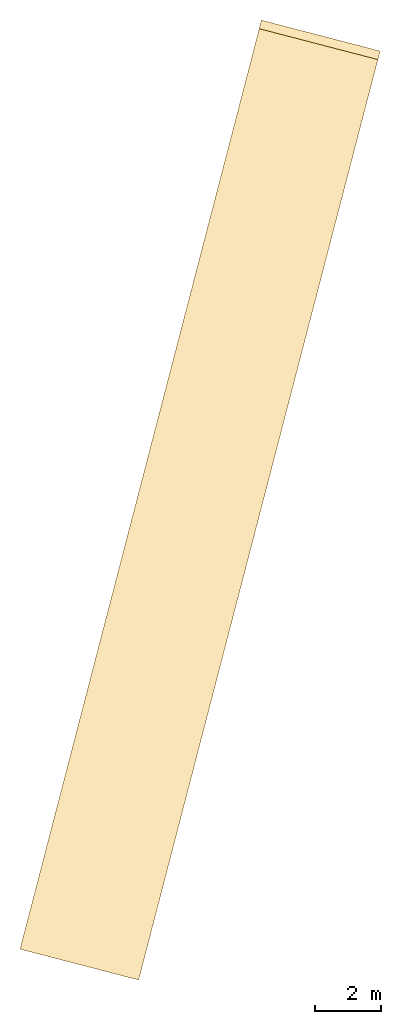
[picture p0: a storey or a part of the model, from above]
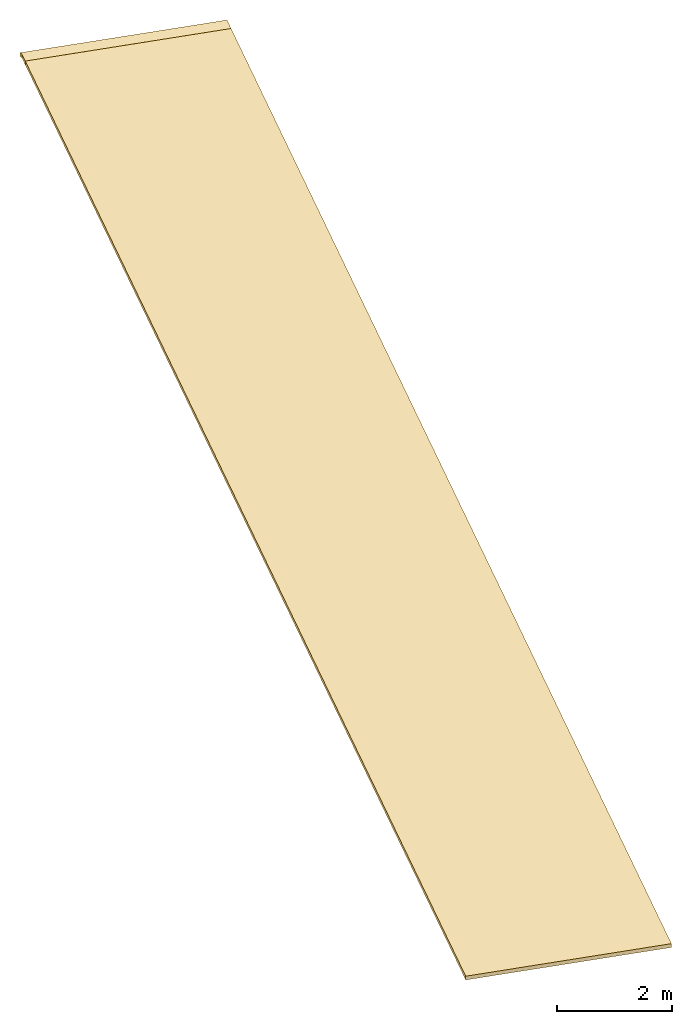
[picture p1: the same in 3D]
Properties of the parts of a building model (IFC2X3)

# File
Description: ViewDefinition [CoordinationView_V2.0, QuantityTakeOffAddOnView]
File name: zv001-a-200-1-0003.ifc (Edited by Naviate Simple BIM 2022 version 6)
Time: 2026-01-09T13:08:05+01:00
Written by: ODA SDAI 24.12
Made in: Autodesk Revit 25.4.30.30 (ENU) - IFC 25.4.0.27

# IfcProject, 10001574
LongName: ENZV Kommersielt areal innland (KAI); Phase: Hovedprosjekt: 01.12.2018

# IfcSite (2)
RefElevation: 0 mm
Name | RefLatitude | RefLongitude
ENZV | 59, 54, 57, 601318 | 10, 44, 59, 999999 | Identity Data - Inventarnr.: ZV001; Building Name: ZV001; CQIncludeDoorSwing: no; CQIncludeRoomNumber: no; CQIncludeRoomNumberWindows: no; CQIncludeWindowSwing: no; Workset: Project Info; Organization Description: BIM 360://Avinor - Stavanger lufthavn/ENZV_ARK_bygg A.rvt; Prosjekt: Stavanger lufthavn, Sola; Text - 02_IfcSite: STAVANGER LUFTHAVN; 01_Modellfil: zv001-a-200-1-0003.rvt; Prosjektleder: Livar Husveg; Tiltaket gjelder: Kommersielt areal innland, KAI; Other - Project Number: 10001574; CQDoorSwingCodes: Left=V;Right=H;notMirrored =L;mirrored =R; Project Issue Date: Tilbudsprosjekt: 22.07.2018; CQWindowSwingCodes: Left=Rettv.;Right=Speilv.; Category: Project Information; Project Address: Enter address here; CQPhaseFilter: Existing:True;New Construction:True;Fase 2.0:True;Fase 3.0:True;Fase 3.9:True;Fase 4.0:True;Fase 5.1:True;Fase 5.2:True;Fase 5.3:True;Fase 5.4:True;Fase 5.9:True;Fase 5.10:True;Fase plot tegninger:True;Fase 6.0:True;; CQIncludeTemporaryDoors: no; Project Name: ENZV Kommersielt areal innland (KAI); Project Status: Hovedprosjekt: 01.12.2018; Tiltakshavers navn: Livar Husveg
Default | 42, 24, 53, 508911 | -71, -15, -29, -58837 | Pset_ProductRequirements - Category: Project Information

# IfcBuilding (2)
Name | NumberOfStoreys
ZV001 | 8 | LongName: ZV001; Identity Data - Inventarnr.: ZV001; Building Name: ZV001; CQIncludeDoorSwing: no; CQIncludeRoomNumber: no; CQIncludeRoomNumberWindows: no; CQIncludeWindowSwing: no; Workset: Project Info; Organization Description: BIM 360://Avinor - Stavanger lufthavn/ENZV_ARK_bygg A.rvt; Prosjekt: Stavanger lufthavn, Sola; Text - 02_IfcSite: STAVANGER LUFTHAVN; 01_Modellfil: zv001-a-200-1-0003.rvt; Prosjektleder: Livar Husveg; Tiltaket gjelder: Kommersielt areal innland, KAI; Other - Project Number: 10001574; CQDoorSwingCodes: Left=V;Right=H;notMirrored =L;mirrored =R; Project Issue Date: Tilbudsprosjekt: 22.07.2018; CQWindowSwingCodes: Left=Rettv.;Right=Speilv.; Category: Project Information; Project Address: Enter address here; CQPhaseFilter: Existing:True;New Construction:True;Fase 2.0:True;Fase 3.0:True;Fase 3.9:True;Fase 4.0:True;Fase 5.1:True;Fase 5.2:True;Fase 5.3:True;Fase 5.4:True;Fase 5.9:True;Fase 5.10:True;Fase plot tegninger:True;Fase 6.0:True;; CQIncludeTemporaryDoors: no; Project Name: ENZV Kommersielt areal innland (KAI); Project Status: Hovedprosjekt: 01.12.2018; Tiltakshavers navn: Livar Husveg
 | 4 | Pset_ProductRequirements - Category: Project Information

# IfcBuildingStorey: Level:8mm Nivåhode Lokale Koter (2)
In: ZV001
Identity Data - Structural: no; Building Story: yes; Workset: Shared Levels and Grids
Graphics(Type) - Line Pattern: Centre; Color: 0; Symbol at End 1 Default: no; Symbol at End 2 Default: yes; Line Weight: 1; Symbol: View - Nivåhode1 : Nivåhode Trekant 2
Identity Data(Type) - Workset: Level Types; Type Name: 8mm Nivåhode Lokale Koter
Constraints(Type) - Elevation Base: Project Base Point
Other - Type Id: 305; Category: Levels; Family and Type: Level: 8mm Nivåhode Lokale Koter; Family: Level; Type: 8mm Nivåhode Lokale Koter
Pset_AirSideSystemInformation - sets with these values: 2
Other(Type) - Category: Levels; Family Name: Level
Phasing - Fagkode: ARK
Name | LongName = Identity Data, Name = Pset_AirSideSystemInformation, Name = Etasjekoder | Elevation (mm) = Constraints, Elevation (mm) | Computation Height (mm)
H01 | H01 | 5100 | 1200
H02 | H02 | 9300 | 0

# IfcBuildingStorey: Level:NO_Nivå_meter-Project, PLAN 01. ETG
LongName: PLAN 01. ETG; Elevation: 5100 mm
Pset_AirSideSystemInformation - Name: PLAN 01. ETG
Pset_ProductRequirements - Name: PLAN 01. ETG; Category: Levels

# IfcBuildingElementProxy: Generic Models 4:Generic Models 4, Generic Models 4:Generic Models 4:919170
In: PLAN 01. ETG
Type - Material: Hvit
Type - Other - Category: Generic Models; Family Name: Generic Models 4
Type - Identity Data - Type Name: Generic Models 4; Workset: Workset1
ePset_LocationTool - Splitting: RESULT
ePset_SimplebimBasicQuantities - Height (Simplebim): 450 mm; Thickness (Simplebim): 612 mm; Length (Simplebim): 1824 mm; Area, largest surface, net (Simplebim): 1.00146 m2; Volume, net (Simplebim): 0.389924 m3
ePset_Simplebim - Assembly Level: Leaf
Pset_ProductRequirements - Category: Generic Models
Pset_BuildingElementProxyCommon - Reference: Generic Models 4; sets with these values: 2

# IfcBuildingElementProxy: karusseldør Bund7:karusseldør Bund, karusseldør Bund7:karusseldør Bund:3024298
In: H01
Type - Material: Aluminium, Glass, <Unnamed>
Type - Other - Category: Generic Models; Family Name: karusseldør Bund7
Type - Identity Data - Type Name: karusseldør Bund; Workset: Workset1
Constraints - Moves With Nearby Elements: no
Pset_BuildingElementProxyCommon - Reference: karusseldør Bund; sets with these values: 2
Phasing - Phase Created: Fase 1 - Som bygget
ePset_LocationTool - Splitting: RESULT
ePset_Simplebim - Assembly Level: Leaf
ePset_SimplebimBasicQuantities - Area, largest surface, net (Simplebim): 0.935324 m2; Volume, net (Simplebim): 0.330344 m3; Thickness (Simplebim): 896 mm; Length (Simplebim): 1751 mm; Height (Simplebim): 2918 mm
Other - Type Id: 3024296; Family and Type: karusseldør Bund7: karusseldør Bund; Type: karusseldør Bund; Family: karusseldør Bund7
Group: Model Group:Karusseldør YK01:3024403

# IfcColumn: NO_S-Column_Precast_Round:Pullert ø350, NO_S-Column_Precast_Round:Pullert ø350:886020
In: PLAN 01. ETG
Type - PredefinedType: COLUMN; Material: NO_Betong - Prefab
Type - Pset_ColumnCommon - Reference: Pullert ø350; IsExternal: no; LoadBearing: yes
Type - Pset_ProductRequirements - Category: Structural Columns
Type - Pset_QuantityTakeOff - Reference: Pullert ø350
Type - Pset_ReinforcementBarPitchOfColumn - Reference: Pullert ø350
Pset_ReinforcementBarPitchOfColumn - sets with these values: 2
ePset_SimplebimBasicQuantities - Width (Simplebim): 350 mm; Depth (Simplebim): 350 mm; Volume, net (Simplebim): 0.129227 m3; Area, sides, net (Simplebim): 1.48252 m2; Weight, as steel (Simplebim): 1014.43 kg; Height (Simplebim): 1350 mm
ePset_LocationTool - Splitting: ORIGINAL
AVINOR - 03_Ansvar: RIB Norconsult; 06_Omrade: ZV000; 05_ID-nummer: +ZV000=725.0015-QM0002; 01_Lufthavnkode: ENZV; 02_Prosjekt: 10002213
ePset_Simplebim - Assembly Level: Leaf

# IfcColumn: Søyle Betong Sirkulær:350 (4)
In: H01
Type - PredefinedType: COLUMN; Material: Betong Plasstøpt - B35
Type - Other - Category: Structural Columns; Family Name: Søyle Betong Sirkulær; k1: 3.14159
Type - Dimensions - D: 350 mm; Perimeter: 1099.56 mm
Type - Identity Data - Type Name: 350; URL: www.cad-q.no; Workset: Family : Structural Columns : Søyle Betong Sirkulær
Type - Structural - Section Shape: 0
Type - Pset_ColumnCommon - LoadBearing: yes
Phasing - Phase Created: Fase 1 - Som bygget
Pset_QuantityTakeOff - Reference: 350; sets with these values: 2
Pset_ColumnCommon - IsExternal: no; Reference: 350
Identity Data - Has Association: yes; Workset: Workset1
Other - Family and Type: Søyle Betong Sirkulær: 350; Type Id: 414188; Family: Søyle Betong Sirkulær; Type: 350
Structural - Rebar Cover - Top Face: Rebar Cover 1 <25 mm>; Rebar Cover - Other Faces: Rebar Cover 1 <25 mm>; Rebar Cover - Bottom Face: Rebar Cover 1 <25 mm>
Constraints - Room Bounding: no; Moves With Grids: no; Level: H01; Base Level: H01; Top Level: H02; Column Style: Vertical
ePset_SimplebimBasicQuantities - Volume, net (Simplebim): 0.335032 m3; Area, sides, net (Simplebim): 3.84357 m2; Weight, as steel (Simplebim): 2630 kg; Width (Simplebim): 350 mm; Depth (Simplebim): 350 mm; Height (Simplebim): 3500 mm
ePset_Simplebim - Assembly Level: Leaf
Materials and Finishes - Structural Material: Betong Plasstøpt - B35
ePset_LocationTool - Splitting: RESULT
Name (Søyle Betong Sirkulær:350:...) | Column Location Mark
3049593 | P3-CM03
3049595 | P3-CM04
3049607 | P3-CM05
3049619 | P3-CM06 | Group: Model Group:Array Group 3:3049621

# IfcCovering: Compound Ceiling:ENZV_H01_Perf gipshimling 600x600mm (3)
Type - PredefinedType: CEILING
Type - Other - Category: Ceilings; Family Name: Compound Ceiling
Type - Construction - Thickness: 80 mm
Type - Graphics - Coarse Scale Fill Color: 0
Type - Identity Data - Type Mark: H-03; Type Name: ENZV_H01_Perf gipshimling 600x600mm; Workset: Ceiling Types
Type - Analytical Properties - Absorptance: 0.1; Roughness: 1
Type - Pset_CoveringCommon - TotalThickness: 80 mm
ePset_LocationTool - Splitting: RESULT
Phasing - Phase Created: Fase 1 - Som bygget
ePset_SimplebimBasicQuantities - Height (Simplebim): 80 mm
Pset_CoveringCommon - Reference: ENZV_H01_Perf gipshimling 600x600mm; Finish: Systemhimling 600x600mm;
Constraints - Room Bounding: yes
Other - Type: ENZV_H01_Perf gipshimling 600x600mm; Type Id: 389168; Family: Compound Ceiling; Family and Type: Compound Ceiling: ENZV_H01_Perf gipshimling 600x600mm
ePset_Simplebim - Assembly Level: Leaf
Pset_QuantityTakeOff - Reference: ENZV_H01_Perf gipshimling 600x600mm
Identity Data - Workset: Workset1
Name (Compound Ceiling:ENZV_H01_Perf gipshimling 600x600mm:...) | In | Volume, net (Simplebim) (m3) | Area, largest surface, net (Simplebim) (m2) | Width (Simplebim) (mm) | Length (Simplebim) (mm) | Level
3023942 | H02 | 8.49494 | 106.187 | 17552 | 26898 | H02
3049153 | H02 | 0.0789045 | 0.986301 | 2092 | 3338 | H02
3026525 | H01 | 0.469333 | 5.86664 | 3214 | 3946 | H01

# IfcCurtainWall: Curtain Wall:Curtain Wall glass 125mm ut (10)
In: H01
Type - Other - Category: Walls; Family Name: Curtain Wall
Type - Construction - Function: Exterior; Automatically Embed: yes; Join Condition: Not Defined
Type - Identity Data - Type Name: Curtain Wall glass 125mm ut; Workset: Curtain Wall Types
Type - Horizontal Grid - Adjust for Mullion Size: no
Type - Vertical Grid - Adjust for Mullion Size: no
Pset_QuantityTakeOff - Reference: Curtain Wall glass 125mm ut
Cross-Section Definition - Cross-Section: Vertical
Structural - Structural Usage: Non-bearing; Structural: no
Constraints - Base is Attached: no; Related to Mass: no; Room Bounding: yes; Top Offset: 0 mm; Top is Attached: no; Base Constraint: H01; Base Offset: 20 mm
Other - Type: Curtain Wall glass 125mm ut; Family and Type: Curtain Wall: Curtain Wall glass 125mm ut; Type Id: 386823; Family: Curtain Wall
ePset_Simplebim - Assembly Level: Topmost
Phasing - Phase Created: Fase 1 - Som bygget
Horizontal Grid - Number: 4; Angle: 0 deg; Offset: 0 mm; Justification: Beginning
Vertical Grid - Angle: 0 deg; Offset: 0 mm; Number: 4; Justification: Beginning
Pset_CurtainWallCommon - Reference: Curtain Wall glass 125mm ut; IsExternal: yes
BaseQuantities - Width: 25 mm
Name (Curtain Wall:Curtain Wall glass 125mm ut:...) | Volume, net (Simplebim) (m3) | ePset_SimplebimBasicQuantities, Height (mm) | Width (mm) | ePset_SimplebimBasicQuantities, Length (mm) | Unconnected Height (mm) = BaseQuantities, Height (mm) | CQWallGrossArea (m2) | Workset | Area (m2) = GrossSideArea (m2) | Dimensions, Length (mm)
3028790 | 73.4516 | 12410.4 | 303 | 72064.9 | 12410 | 858.837 | Workset1 | 838.989 | 72110.9 | Identity Data - Has Association: no
3038579 | 2.36117 | 4170 | 4775.25 | 7967.47 | 4170 | 242.024 | Workset1 | 37.6335 | 9024.81
3045456 | 0.613538 | 4170 | 1188.29 | 1754.17 | 4170 | 242.024 | Workset1 | 7.71461 | 1850.03
3045476 | 0.550154 | 4170 | 1162.92 | 1710.59 | 4170 | 242.024 | Workset1 | 7.506 | 1800
3045501 | 0.504609 | 4170 | 1188.35 | 1754.1 | 4170 | 242.024 | Workset1 | 7.7145 | 1850
3045579 | 0.549954 | 4170 | 1188.35 | 1754.1 | 4170 | 242.024 | Workset1 | 7.7145 | 1850
3045609 | 0.527082 | 4170 | 1140.3 | 1670.9 | 4170 | 242.024 | Workset1 | 7.31383 | 1753.92
3045628 | 0.550154 | 4170 | 1162.92 | 1710.59 | 4170 | 242.024 | Workset1 | 7.506 | 1800
3045650 | 0.442854 | 4170 | 1115.23 | 1627.63 | 4170 | 242.024 | Workset1 | 7.10524 | 1703.89
4091180 | 5.41812 | 4170 | 10163.6 | 17298.7 | 4170 | 242.024 | ARK - Innvendige arbeider | 82.5662 | 23853.9

# IfcCurtainWall: Curtain Wall:Glassvegg 24 dB (4)
In: H01
Type - Other - Category: Walls; Family Name: Curtain Wall
Type - Construction - Function: Exterior; Automatically Embed: yes; Join Condition: Not Defined
Type - Identity Data - Type Name: Glassvegg 24 dB; Workset: Curtain Wall Types; Lydklasse: R'w=24 dB; Type Mark: IVG 24 dB
Type - Horizontal Grid - Adjust for Mullion Size: no
Type - Vertical Grid - Adjust for Mullion Size: no
Cross-Section Definition - Cross-Section: Vertical
Other - Family and Type: Curtain Wall: Glassvegg 24 dB; Type: Glassvegg 24 dB; Type Id: 128838; Family: Curtain Wall
Constraints - Base is Attached: no; Related to Mass: no; Room Bounding: yes; Top Offset: 0 mm; Top is Attached: no; Base Constraint: H01
Structural - Structural Usage: Non-bearing; Structural: no
Identity Data - Workset: Workset1
ePset_Simplebim - Assembly Level: Topmost
Pset_CurtainWallCommon - Reference: Glassvegg 24 dB; IsExternal: yes
Phasing - Phase Created: Fase 1 - Som bygget
Horizontal Grid - Number: 4; Angle: 0 deg; Offset: 0 mm; Justification: Beginning
Vertical Grid - Angle: 0 deg; Offset: 0 mm; Number: 4; Justification: Beginning
Pset_QuantityTakeOff - Reference: Glassvegg 24 dB
BaseQuantities - Width: 25 mm
Name (Curtain Wall:Glassvegg 24 dB:...) | ePset_SimplebimBasicQuantities, Length (mm) | Width (mm) | Volume, net (Simplebim) (m3) | ePset_SimplebimBasicQuantities, Height (mm) = Unconnected Height (mm) = BaseQuantities, Height (mm) | Base Offset (mm) | CQWallGrossArea (m2) | Dimensions, Length (mm) | Area (m2) = GrossSideArea (m2)
3024238 | 925.666 | 563.301 | 0.061688 | 3170 | 20 | 3.37605 | 1040 | 3.2968
3024243 | 3142.51 | 1843.2 | 0.217142 | 3170 | 20 | 21.1452 | 3599.79 | 11.4113
3024247 | 581.996 | 364.883 | 0.0475209 | 3170 | 20 | 2.11808 | 643.164 | 2.03883
3024262 | 4415.59 | 2578.21 | 0.0350831 | 292 | 2898 | 1.50667 | 5069.81 | 1.48039

# IfcDoor: Systemveggdør Skyvedør Dobbel med Glassfelt (parametrisk offset):Aluminiumglassfelt Innendørs, Systemveggdør Skyvedør Dobbel med Glassfelt (parametrisk offset):Aluminiumglassfelt Innendørs:3024244
In: H01
Type - ConstructionType: USERDEFINED; ParameterTakesPrecedence: no; Sizeable: no; Material: Glassplater, Aluminium
Type - Other - Category: Doors; Family Name: Systemveggdør Skyvedør Dobbel med Glassfelt (parametrisk offset); CQUnit: pcs
Type - Constraints - CQOriginalSwingDirection: Not Applicable
Type - Construction - Construction Type: AGF Aluminiumsglassfelt; Dørklinke: Dørklinke - Enkel : Rustfritt; Function: Interior
Type - Dimensions - Thickness: 50 mm; Glass Thickness Inner Panel: 10 mm; Glass Thickness Side Panel: 10 mm; Inner Mullion Thickness: 50 mm; Inner Mullion Width: 50 mm; Inset Glass Inner Panel: 10 mm; Inset Glass Side Panels: 10 mm; Offset: 50 mm; Outset Glass Inner Panel: 30 mm; Outset Glass Side Panels: 30 mm; Side Panel Length: 874.5 mm; Side Panel Mullion Width: 50 mm
Type - Identity Data - Type Mark: -; Type Name: Aluminiumglassfelt Innendørs; Workset: Family : Doors : Systemveggdør Skyvedør Dobbel med Glassfelt (parametrisk offset); CQTypeCount: 2; Model: Modulmål
Type - Materials and Finishes - Dørbladmateriale: Aluminium; Glassmateriale: Glassplater
Type - Analytical Properties - Analytic Construction: <None>; Define Thermal Properties by: Schematic Type
Type - Pset_ConcreteElementGeneral - ConstructionType: AGF Aluminiumsglassfelt
OverallHeight: 2704 mm; OverallWidth: 3599.79 mm
ePset_SimplebimBasicQuantities - Area (Simplebim): 9.73383 m2; Height (Simplebim): 2704 mm; Length, frame (Simplebim): 9007.79 mm; Width (Simplebim): 3599.79 mm
Constraints - Level: H01
Phasing - Phase Created: Fase 1 - Som bygget
Pset_QuantityTakeOff - Reference: Aluminiumglassfelt Innendørs
Pset_DoorCommon - Reference: Aluminiumglassfelt Innendørs; IsExternal: no
Other - Family and Type: Systemveggdør Skyvedør Dobbel med Glassfelt (parametrisk offset): Aluminiumglassfelt Innendørs; Type: Aluminiumglassfelt Innendørs; Type Id: 2906429; Family: Systemveggdør Skyvedør Dobbel med Glassfelt (parametrisk offset); Host Id: 3024243
Identity Data - 08_Brannkrav: -; Workset: Workset1; Mark: B1003.4
ePset_Simplebim - Assembly Level: Leaf
ePset_LocationTool - Splitting: ORIGINAL
AVINOR - 08_Brannkrav: -
Dimensions - Height: 2704 mm; Volume: 0.156505 m3; Area: 9.73383 m2; Width: 3599.79 mm
BaseQuantities - Height: 2704 mm; Area: 9.73383 m2; Width: 3599.79 mm

# IfcDoor: Tofløyet Glassfelt:YDG13_15.5x21M, Tofløyet Glassfelt:YDG13_15.5x21M:3045538
In: H01
Type - OperationType: DOUBLE_DOOR_SINGLE_SWING; ConstructionType: USERDEFINED; ParameterTakesPrecedence: no; Sizeable: no; Material: Rustfritt Stål, Glassplater, Glassdør med alukarm, Aluminium
Type - IfcDoorPanelProperties - PanelOperation: SWINGING
Type - Other - Category: Doors; Family Name: Tofløyet Glassfelt; Karmfalsbredde: 30 mm; M_Height: 21; M_Width: 16
Type - Constraints - Marker slagretning i plan: yes
Type - Construction - Construction Type: AGF Aluminiumsglassfelt; Dørblad i plan: no; Dørklinke: Dørklinke - Enkel : Rustfritt; Function: Exterior; Terskel: no; Terskeltype: Terskeltype; Wall Closure: By host
Type - Dimensions - Karmbredde: 42 mm; Karmdybde: 100 mm; Karmprofil: 12 mm; Rough Height: 2090 mm; Rough Width: 1550 mm; Thickness: 40 mm; Panelramme: 100 mm; UK Glass: 150 mm
Type - Identity Data - DoorBasalOpening: V; Fire Rating: -; Type Mark: YDG13; Type Name: YDG13_15.5x21M; URL: www.cad-q.no; Workset: Family : Doors : Tofløyet Glassfelt; Description: Tofløyet slagdør i systemfasade; Model: 1550 x 2090
Type - Materials and Finishes - Dørbladmateriale: Glassdør med alukarm; Karmmateriale: Aluminium; Terskelmateriale: Rustfritt Stål
Type - Analytical Properties - Analytic Construction: <None>; Define Thermal Properties by: Schematic Type
Type - Pset_ConcreteElementGeneral - FireRating: -; ConstructionType: AGF Aluminiumsglassfelt
Type - Pset_DoorCommon - FireRating: -
Type - Text - Terskeltype: Rustfritt stål
OverallHeight: 2110 mm; OverallWidth: 1570 mm
Identity Data - Comments: Inkl. tett alu sidefelt; CQSwingDirection: V, utadslående; 08_Brannkrav: -; CQAcousticRequirement: Rw+c5_fly≥32dB; Workset: Workset1; CQFireRequirement: Ikke krav; Mark: B1021.08
Pset_DoorCommon - Reference: YDG13_15.5x21M; IsExternal: yes
Text - Skilt: Blindskilt utside; U-verdi: 1,2 W/m2K; Vrider: Stang Ø30, L:700, RF304 børstet; UPS: X; Description S: X; Automatisk åpning av dør ved aktivering røykvifter: X; Låskasse: FG godkjent, skallsikring; Sylinder: System K1 til K4 innside; Fargekode: Natureloksert
Phasing - Phase Created: Fase 1 - Som bygget
ePset_LocationTool - Splitting: ORIGINAL
ePset_SimplebimBasicQuantities - Area (Simplebim): 3.2395 m2; Length, frame (Simplebim): 5730 mm; Height (Simplebim): 2090 mm; Width (Simplebim): 1550 mm
Constraints - Sill Height: 0 mm; Level: H01
ePset_Simplebim - Assembly Level: Leaf
Pset_QuantityTakeOff - Reference: YDG13_15.5x21M
AVINOR - 08_Brannkrav: -
Dimensions - Volume: 0.0805 m3; Veggtykkelse: 50 mm; Area: 4.44709 m2; Spalte Side: 10 mm; Innsetting: 20 mm; Spalte Topp: 20 mm; Width: 1570 mm; Height: 2110 mm
Other - Type: YDG13_15.5x21M; Sparkeplate: H:200; Family: Tofløyet Glassfelt; Family and Type: Tofløyet Glassfelt: YDG13_15.5x21M; Type Id: 2906824; Panikkbeslag: X; Automatisk åpning av lås ved brannalarm: X; Innsetoffset: 1020 mm; Head Height: 2110 mm; Host Id: 3045537
BaseQuantities - Area: 3.3127 m2; Width: 1570 mm; Height: 2110 mm

# IfcGroup: Model Group:Array Group 3, Model Group:Array Group 3:3049621
Identity Data - Workset: Workset1
Constraints - Origin Level Offset: 0 mm; Reference Level: H01
Other(Type) - Category: Model Groups; Family Name: Model Group
Identity Data(Type) - Type Name: Array Group 3; Workset: Workset1
Other - Category: Model Groups; Type: Array Group 3; Family: Model Group; Type Id: 2901797; Family and Type: Model Group: Array Group 3

# IfcGroup: Model Group:Karusseldør YK01, Model Group:Karusseldør YK01:3024403
Identity Data - Workset: Workset1
Constraints - Origin Level Offset: 0 mm; Reference Level: H01
Other(Type) - Category: Model Groups; Family Name: Model Group
Identity Data(Type) - Type Name: Karusseldør YK01; Workset: Workset1
Other - Category: Model Groups; Family: Model Group; Type: Karusseldør YK01; Family and Type: Model Group: Karusseldør YK01; Type Id: 2875737

# IfcMember: Rectangular Mullion:ENZV_300x50mm_offset 70 (7)
In: H01
Type - PredefinedType: MULLION; Material: Aluminium
Type - Other - Category: Curtain Wall Mullions; Family Name: Rectangular Mullion
Type - Constraints - Angle: 0 deg; Offset: 67 mm
Type - Construction - Corner Mullion: no; Position: Perpendicular to Face; Profile: System Mullion Profile: Rectangular; Thickness: 303 mm
Type - Dimensions - Width on side 1: 25 mm; Width on side 2: 25 mm
Type - Identity Data - Type Name: ENZV_300x50mm_offset 70; Workset: Family : Curtain Wall Mullions : Rectangular Mullion
Type - Materials and Finishes - Material: Aluminium
Pset_QuantityTakeOff - Reference: ENZV_300x50mm_offset 70
Other - Family: Rectangular Mullion; Type: ENZV_300x50mm_offset 70; Host Id: 3028790; Type Id: 2906612; Family and Type: Rectangular Mullion: ENZV_300x50mm_offset 70
Identity Data - Workset: Workset1
Pset_MemberCommon - Reference: ENZV_300x50mm_offset 70; IsExternal: yes
Constraints - Level: H01
ePset_Simplebim - Assembly Level: Leaf
Phasing - Phase Created: Fase 1 - Som bygget
Name (Rectangular Mullion:ENZV_300x50mm_offset 70:...) | Volume, net (Simplebim) (m3) | Weight, as steel (Simplebim) (kg) | Area, sides, net (Simplebim) (m2) | Width (Simplebim) (mm) | Length (Simplebim) (mm) | Height (Simplebim) (mm) | Splitting | Span (mm) = Dimensions, Length (mm) = BaseQuantities, Length (mm) | Volume (m3) | Area (m2) = CrossSectionArea (m2) | NetVolume (m3)
3031881 | 0.0317392 | 249.153 | 1.50937 | 50 | 303 | 2095 | ORIGINAL | 2095 | 0.0317393 | 0.754685 | 0.0317392
3038323 | 0.00909 | 71.3565 | 0.4539 | 50 | 303 | 600 | ORIGINAL | 600 | 0.00909 | 0.22695 | 0.00909
3039097 | 0.00068175 | 5.35174 | 0.06207 | 50 | 303 | 45 | ORIGINAL | 45 | 0.00068175 | 0.031035 | 0.00068175
3039562 | 0.0050803 | 39.8804 | 0.267045 | 50 | 303 | 335.333 | ORIGINAL | 335.333 | 0.0050803 | 0.133523 | 0.0050803
3045294 | 0.00515212 | 40.4442 | 0.275161 | 50 | 269 | 405 | RESULT
3048168 | 0.00177158 | 13.9069 | 0.110002 | 222 | 239 | 50 | RESULT
3048167 | 0.00177146 | 13.9059 | 0.109935 | 220 | 240 | 50 | RESULT

# IfcMember: Rectangular Mullion:ENZV_304x50mm (52)
In: H01
Type - PredefinedType: MULLION; Material: Aluminium
Type - Other - Category: Curtain Wall Mullions; Family Name: Rectangular Mullion
Type - Constraints - Angle: 0 deg; Offset: 0 mm
Type - Construction - Corner Mullion: no; Position: Perpendicular to Face; Profile: System Mullion Profile: Rectangular; Thickness: 304 mm
Type - Dimensions - Width on side 1: 25 mm; Width on side 2: 25 mm
Type - Identity Data - Type Name: ENZV_304x50mm; Workset: Family : Curtain Wall Mullions : Rectangular Mullion
Type - Materials and Finishes - Material: Aluminium
Pset_MemberCommon - Reference: ENZV_304x50mm; IsExternal: yes
Other - Type: ENZV_304x50mm; Family: Rectangular Mullion; Type Id: 2906403; Family and Type: Rectangular Mullion: ENZV_304x50mm
Constraints - Level: H01
Pset_QuantityTakeOff - Reference: ENZV_304x50mm
ePset_Simplebim - Assembly Level: Leaf
Phasing - Phase Created: Fase 1 - Som bygget
Name (Rectangular Mullion:ENZV_304x50mm:...) | Workset | Host Id | Splitting | Area, sides, net (Simplebim) (m2) | Weight, as steel (Simplebim) (kg) | Volume, net (Simplebim) (m3) | Height (Simplebim) (mm) | Width (Simplebim) (mm) | Length (Simplebim) (mm)
3045474 | Workset1 | 3045456 | ORIGINAL | 1.2658 | 208.123 | 0.0265125 | 50 | 303 | 1750 | Pset_MemberCommon - Span: 1750.01 mm; Dimensions - Volume: 0.0266002 m3; Area: 0.634705 m2; Length: 1750.01 mm; BaseQuantities - NetVolume: 0.0266002 m3; CrossSectionArea: 0.634705 m2; Length: 1750.01 mm
3045494 | Workset1 | 3045476 | ORIGINAL | 1.2658 | 208.123 | 0.0265125 | 50 | 303 | 1750 | Pset_MemberCommon - Span: 1749.99 mm; Dimensions - Volume: 0.0265998 m3; Area: 0.634695 m2; Length: 1749.99 mm; BaseQuantities - NetVolume: 0.0265998 m3; CrossSectionArea: 0.634695 m2; Length: 1749.99 mm
3045516 | Workset1 | 3045501 | ORIGINAL | 1.50937 | 249.153 | 0.0317392 | 2095 | 50 | 303 | Pset_MemberCommon - Span: 2095 mm; Dimensions - Volume: 0.031844 m3; Area: 0.75683 m2; Length: 2095 mm; BaseQuantities - NetVolume: 0.031844 m3; CrossSectionArea: 0.75683 m2; Length: 2095 mm
3045517 | Workset1 | 3045501 | ORIGINAL | 1.50937 | 249.153 | 0.0317392 | 2095 | 50 | 303 | Pset_MemberCommon - Span: 2095 mm; Dimensions - Volume: 0.031844 m3; Area: 0.75683 m2; Length: 2095 mm; BaseQuantities - NetVolume: 0.031844 m3; CrossSectionArea: 0.75683 m2; Length: 2095 mm
3045527 | Workset1 | 3045501 | ORIGINAL | 1.14225 | 187.311 | 0.0238613 | 50 | 303 | 1575 | Pset_MemberCommon - Span: 1575 mm; Dimensions - Volume: 0.02394 m3; Area: 0.57275 m2; Length: 1575 mm; BaseQuantities - NetVolume: 0.02394 m3; CrossSectionArea: 0.57275 m2; Length: 1575 mm
3045532 | Workset1 | 3045501 | ORIGINAL | 0.15385 | 20.8123 | 0.00265125 | 50 | 175 | 303 | Pset_MemberCommon - Span: 175 mm; Dimensions - Volume: 0.00266 m3; Area: 0.07715 m2; Length: 175 mm; BaseQuantities - NetVolume: 0.00266 m3; CrossSectionArea: 0.07715 m2; Length: 175 mm
3045533 | Workset1 | 3045501 | ORIGINAL | 1.49172 | 246.18 | 0.0313605 | 2070 | 50 | 303 | Pset_MemberCommon - Span: 2070 mm; Dimensions - Volume: 0.031464 m3; Area: 0.74798 m2; Length: 2070 mm; BaseQuantities - NetVolume: 0.031464 m3; CrossSectionArea: 0.74798 m2; Length: 2070 mm
3045534 | Workset1 | 3045501 | ORIGINAL | 1.1246 | 184.338 | 0.0234825 | 50 | 303 | 1550 | Pset_MemberCommon - Span: 1550 mm; Dimensions - Volume: 0.02356 m3; Area: 0.5639 m2; Length: 1550 mm; BaseQuantities - NetVolume: 0.02356 m3; CrossSectionArea: 0.5639 m2; Length: 1550 mm
3045594 | Workset1 | 3045579 | ORIGINAL | 1.50937 | 249.153 | 0.0317392 | 2095 | 50 | 303 | Pset_MemberCommon - Span: 2095 mm; Dimensions - Volume: 0.031844 m3; Area: 0.75683 m2; Length: 2095 mm; BaseQuantities - NetVolume: 0.031844 m3; CrossSectionArea: 0.75683 m2; Length: 2095 mm
3045595 | Workset1 | 3045579 | ORIGINAL | 1.50937 | 249.153 | 0.0317392 | 2095 | 50 | 303 | Pset_MemberCommon - Span: 2095 mm; Dimensions - Volume: 0.031844 m3; Area: 0.75683 m2; Length: 2095 mm; BaseQuantities - NetVolume: 0.031844 m3; CrossSectionArea: 0.75683 m2; Length: 2095 mm
3045605 | Workset1 | 3045579 | ORIGINAL | 1.2658 | 208.123 | 0.0265125 | 50 | 303 | 1750 | Pset_MemberCommon - Span: 1750.01 mm; Dimensions - Volume: 0.0266002 m3; Area: 0.634705 m2; Length: 1750.01 mm; BaseQuantities - NetVolume: 0.0266002 m3; CrossSectionArea: 0.634705 m2; Length: 1750.01 mm
3045623 | Workset1 | 3045609 | ORIGINAL | 1.20137 | 197.345 | 0.0251395 | 50 | 304 | 1653.92 | Pset_MemberCommon - Span: 1653.92 mm; Dimensions - Volume: 0.0251395 m3; Area: 0.600686 m2; Length: 1653.92 mm; BaseQuantities - NetVolume: 0.0251395 m3; CrossSectionArea: 0.600686 m2; Length: 1653.92 mm
3045646 | Workset1 | 3045628 | ORIGINAL | 1.2658 | 208.123 | 0.0265125 | 50 | 303 | 1750 | Pset_MemberCommon - Span: 1749.99 mm; Dimensions - Volume: 0.0265998 m3; Area: 0.634695 m2; Length: 1749.99 mm; BaseQuantities - NetVolume: 0.0265998 m3; CrossSectionArea: 0.634695 m2; Length: 1749.99 mm
3045664 | Workset1 | 3045650 | ORIGINAL | 1.20137 | 197.345 | 0.0251395 | 50 | 304 | 1653.92 | Pset_MemberCommon - Span: 1653.89 mm; Dimensions - Volume: 0.0251392 m3; Area: 0.600678 m2; Length: 1653.89 mm; BaseQuantities - NetVolume: 0.0251392 m3; CrossSectionArea: 0.600678 m2; Length: 1653.89 mm
4091235 | ARK - Innvendige arbeider | 4091180 | ORIGINAL | 1.2658 | 208.123 | 0.0265125 | 50 | 303 | 1750 | Pset_MemberCommon - Span: 1750.04 mm; Dimensions - Volume: 0.0266006 m3; Area: 0.634714 m2; Length: 1750.04 mm; BaseQuantities - NetVolume: 0.0266006 m3; CrossSectionArea: 0.634714 m2; Length: 1750.04 mm
4091236 | ARK - Innvendige arbeider | 4091180 | ORIGINAL | 1.2658 | 208.123 | 0.0265125 | 50 | 303 | 1750 | Pset_MemberCommon - Span: 1750 mm; Dimensions - Volume: 0.0266 m3; Area: 0.6347 m2; Length: 1750 mm; BaseQuantities - NetVolume: 0.0266 m3; CrossSectionArea: 0.6347 m2; Length: 1750 mm
4091237 | ARK - Innvendige arbeider | 4091180 | ORIGINAL | 1.2658 | 208.123 | 0.0265125 | 50 | 303 | 1750 | Pset_MemberCommon - Span: 1750 mm; Dimensions - Volume: 0.0266 m3; Area: 0.6347 m2; Length: 1750 mm; BaseQuantities - NetVolume: 0.0266 m3; CrossSectionArea: 0.6347 m2; Length: 1750 mm
4091238 | ARK - Innvendige arbeider | 4091180 | ORIGINAL | 1.2658 | 208.123 | 0.0265125 | 50 | 303 | 1750 | Pset_MemberCommon - Span: 1750 mm; Dimensions - Volume: 0.0266 m3; Area: 0.6347 m2; Length: 1750 mm; BaseQuantities - NetVolume: 0.0266 m3; CrossSectionArea: 0.6347 m2; Length: 1750 mm
4091239 | ARK - Innvendige arbeider | 4091180 | ORIGINAL | 1.2658 | 208.123 | 0.0265125 | 50 | 303 | 1750 | Pset_MemberCommon - Span: 1750 mm; Dimensions - Volume: 0.0266 m3; Area: 0.6347 m2; Length: 1750 mm; BaseQuantities - NetVolume: 0.0266 m3; CrossSectionArea: 0.6347 m2; Length: 1750 mm
4091240 | ARK - Innvendige arbeider | 4091180 | ORIGINAL | 1.2658 | 208.123 | 0.0265125 | 50 | 303 | 1750 | Pset_MemberCommon - Span: 1750 mm; Dimensions - Volume: 0.0266 m3; Area: 0.6347 m2; Length: 1750 mm; BaseQuantities - NetVolume: 0.0266 m3; CrossSectionArea: 0.6347 m2; Length: 1750 mm
4091241 | ARK - Innvendige arbeider | 4091180 | ORIGINAL | 1.2658 | 208.123 | 0.0265125 | 50 | 303 | 1750 | Pset_MemberCommon - Span: 1750 mm; Dimensions - Volume: 0.0266 m3; Area: 0.6347 m2; Length: 1750 mm; BaseQuantities - NetVolume: 0.0266 m3; CrossSectionArea: 0.6347 m2; Length: 1750 mm
4091242 | ARK - Innvendige arbeider | 4091180 | ORIGINAL | 1.2658 | 208.123 | 0.0265125 | 50 | 303 | 1750 | Pset_MemberCommon - Span: 1750 mm; Dimensions - Volume: 0.0266 m3; Area: 0.6347 m2; Length: 1750 mm; BaseQuantities - NetVolume: 0.0266 m3; CrossSectionArea: 0.6347 m2; Length: 1750 mm
4091243 | ARK - Innvendige arbeider | 4091180 | ORIGINAL | 1.2658 | 208.123 | 0.0265125 | 50 | 303 | 1750 | Pset_MemberCommon - Span: 1750 mm; Dimensions - Volume: 0.0266 m3; Area: 0.6347 m2; Length: 1750 mm; BaseQuantities - NetVolume: 0.0266 m3; CrossSectionArea: 0.6347 m2; Length: 1750 mm
4091244 | ARK - Innvendige arbeider | 4091180 | ORIGINAL | 1.2658 | 208.123 | 0.0265125 | 50 | 303 | 1750 | Pset_MemberCommon - Span: 1750 mm; Dimensions - Volume: 0.0266 m3; Area: 0.6347 m2; Length: 1750 mm; BaseQuantities - NetVolume: 0.0266 m3; CrossSectionArea: 0.6347 m2; Length: 1750 mm
4091245 | ARK - Innvendige arbeider | 4091180 | ORIGINAL | 1.2658 | 208.123 | 0.0265125 | 50 | 303 | 1750 | Pset_MemberCommon - Span: 1750 mm; Dimensions - Volume: 0.0266 m3; Area: 0.6347 m2; Length: 1750 mm; BaseQuantities - NetVolume: 0.0266 m3; CrossSectionArea: 0.6347 m2; Length: 1750 mm
3045603 | Workset1 | 3045579 | RESULT | 0.955022 | 154.659 | 0.0197018 | 1385 | 50 | 285
3045620 | Workset1 | 3045609 | RESULT | 2.35442 | 388.182 | 0.0494499 | 3480 | 50 | 284
3045624 | Workset1 | 3045609 | RESULT | 2.3544 | 388.178 | 0.0494495 | 3480 | 50 | 284
3045641 | Workset1 | 3045628 | RESULT | 2.36359 | 389.958 | 0.0496761 | 3480 | 50 | 285
3045642 | Workset1 | 3045628 | RESULT | 2.3636 | 389.959 | 0.0496763 | 3480 | 50 | 285
3045661 | Workset1 | 3045650 | RESULT | 2.36304 | 389.851 | 0.0496625 | 3480 | 50 | 285
3045604 | Workset1 | 3045579 | RESULT | 0.955014 | 154.658 | 0.0197016 | 1385 | 50 | 285
4091217 | ARK - Innvendige arbeider | 4091180 | RESULT | 2.35304 | 387.916 | 0.049416 | 3480 | 50 | 284
4091218 | ARK - Innvendige arbeider | 4091180 | RESULT | 2.35304 | 387.916 | 0.049416 | 3480 | 50 | 284
4091219 | ARK - Innvendige arbeider | 4091180 | RESULT | 2.35304 | 387.916 | 0.049416 | 3480 | 50 | 284
4091220 | ARK - Innvendige arbeider | 4091180 | RESULT | 2.35304 | 387.916 | 0.049416 | 3480 | 50 | 284
4091221 | ARK - Innvendige arbeider | 4091180 | RESULT | 2.35304 | 387.916 | 0.049416 | 3480 | 50 | 284
4091222 | ARK - Innvendige arbeider | 4091180 | RESULT | 2.35304 | 387.916 | 0.049416 | 3480 | 50 | 284
4091223 | ARK - Innvendige arbeider | 4091180 | RESULT | 2.35304 | 387.916 | 0.049416 | 3480 | 50 | 284
4091234 | ARK - Innvendige arbeider | 4091180 | RESULT | 2.35305 | 387.917 | 0.0494162 | 3480 | 50 | 284
3045469 | Workset1 | 3045456 | RESULT | 2.3627 | 389.785 | 0.0496542 | 3480 | 50 | 285
3045470 | Workset1 | 3045456 | RESULT | 2.3627 | 389.785 | 0.0496542 | 3480 | 50 | 285
3045499 | Workset1 | 3045456 | RESULT | 2.3633 | 389.9 | 0.0496688 | 3480 | 50 | 285
3045489 | Workset1 | 3045476 | RESULT | 2.363 | 389.843 | 0.0496615 | 3480 | 50 | 285
3045490 | Workset1 | 3045476 | RESULT | 2.36301 | 389.845 | 0.0496617 | 3480 | 50 | 285
3045525 | Workset1 | 3045501 | RESULT | 0.957907 | 155.206 | 0.0197714 | 1385 | 50 | 286
3045526 | Workset1 | 3045501 | RESULT | 0.957899 | 155.204 | 0.0197712 | 1385 | 50 | 286
4091213 | ARK - Innvendige arbeider | 4091180 | RESULT | 2.35304 | 387.916 | 0.049416 | 3480 | 50 | 284
4091214 | ARK - Innvendige arbeider | 4091180 | RESULT | 2.35304 | 387.916 | 0.049416 | 3480 | 50 | 284
4091215 | ARK - Innvendige arbeider | 4091180 | RESULT | 2.35304 | 387.916 | 0.049416 | 3480 | 50 | 284
4091216 | ARK - Innvendige arbeider | 4091180 | RESULT | 2.35304 | 387.916 | 0.049416 | 3480 | 50 | 284
3038645 | Workset1 | 3038579 | RESULT | 1.16112 | 189.031 | 0.0240803 | 50 | 285 | 1695

# IfcMember: Rectangular Mullion:ENZV_50x50mm uten offset (14)
In: H01
Type - PredefinedType: MULLION; Material: Aluminium
Type - Other - Category: Curtain Wall Mullions; Family Name: Rectangular Mullion
Type - Constraints - Angle: 0 deg; Offset: 0 mm
Type - Construction - Corner Mullion: no; Position: Perpendicular to Face; Profile: System Mullion Profile: Rectangular; Thickness: 50 mm
Type - Dimensions - Width on side 1: 25 mm; Width on side 2: 25 mm
Type - Identity Data - Type Name: ENZV_50x50mm uten offset; Workset: Family : Curtain Wall Mullions : Rectangular Mullion
Type - Materials and Finishes - Material: Aluminium
Pset_MemberCommon - IsExternal: yes; Reference: ENZV_50x50mm uten offset
ePset_SimplebimBasicQuantities - Width (Simplebim): 50 mm
Identity Data - Workset: Workset1
Pset_QuantityTakeOff - Reference: ENZV_50x50mm uten offset
Constraints - Level: H01
ePset_Simplebim - Assembly Level: Leaf
Phasing - Phase Created: Fase 1 - Som bygget
Other - Family: Rectangular Mullion; Family and Type: Rectangular Mullion: ENZV_50x50mm uten offset; Type Id: 2906419; Type: ENZV_50x50mm uten offset
Name (Rectangular Mullion:ENZV_50x50mm uten offset:...) | Span (mm) = Dimensions, Length (mm) = BaseQuantities, Length (mm) | Splitting | Height (Simplebim) (mm) | Area, sides, net (Simplebim) (m2) | Length (Simplebim) (mm) | Volume, net (Simplebim) (m3) | Weight, as steel (Simplebim) (kg) | Area (m2) = CrossSectionArea (m2) | Volume (m3) = NetVolume (m3) | Host Id
3024240 | 3170 | ORIGINAL | 3170 | 0.639 | 50 | 0.007925 | 62.2112 | 0.3195 | 0.007925 | 3024238
3024241 | 840 | ORIGINAL | 50 | 0.173 | 840 | 0.0021 | 16.485 | 0.0865 | 0.0021 | 3024238
3024260 | 840 | ORIGINAL | 50 | 0.173 | 840 | 0.0021 | 16.485 | 0.0865 | 0.0021 | 3024238
3024250 | 3499.79 | ORIGINAL | 50 | 0.704958 | 3499.79 | 0.00874947 | 68.6834 | 0.352479 | 0.00874947 | 3024243
3024253 | 241 | ORIGINAL | 241 | 0.0532 | 50 | 0.0006025 | 4.72963 | 0.0266 | 0.0006025 | 3024243
3024254 | 225 | ORIGINAL | 225 | 0.05 | 50 | 0.0005625 | 4.41563 | 0.025 | 0.0005625 | 3024243
3024255 | 241 | ORIGINAL | 241 | 0.0532 | 50 | 0.0006025 | 4.72963 | 0.0266 | 0.0006025 | 3024243
3024256 | 225 | ORIGINAL | 225 | 0.05 | 50 | 0.0005625 | 4.41563 | 0.025 | 0.0005625 | 3024243
3024257 | 3499.79 | ORIGINAL | 50 | 0.704958 | 3499.79 | 0.00874947 | 68.6834 | 0.352479 | 0.00874947 | 3024243
3024245 | 3170 | ORIGINAL | 3170 | 0.639 | 50 | 0.007925 | 62.2112 | 0.3195 | 0.007925 | 3024247
3024258 | 443.164 | ORIGINAL | 50 | 0.0936327 | 443.164 | 0.00110791 | 8.69709 | 0.0468164 | 0.00110791 | 3024247
3024259 | 443.164 | ORIGINAL | 50 | 0.0936327 | 443.164 | 0.00110791 | 8.69709 | 0.0468164 | 0.00110791 | 3024247
3024264 |  | RESULT | 50 | 0.131034 | 630 | 0.00157543 | 12.3671 |  |  | 3024262
3024265 |  | RESULT | 50 | 0.131034 | 630 | 0.00157543 | 12.3671 |  |  | 3024262

# IfcMember: Rectangular Mullion:FAST FELT 150MM (2)
In: H01
Type - PredefinedType: MULLION; Material: Aluminium
Type - Other - Category: Curtain Wall Mullions; Family Name: Rectangular Mullion
Type - Constraints - Angle: 0 deg; Offset: 0 mm
Type - Construction - Corner Mullion: no; Position: Perpendicular to Face; Profile: System Mullion Profile: Rectangular; Thickness: 50 mm
Type - Dimensions - Width on side 1: 75 mm; Width on side 2: 75 mm
Type - Identity Data - Type Name: FAST FELT 150MM; Workset: Family : Curtain Wall Mullions : Rectangular Mullion
Type - Materials and Finishes - Material: Aluminium
Identity Data - Workset: Workset1
ePset_LocationTool - Splitting: ORIGINAL
Other - Family: Rectangular Mullion; Type: FAST FELT 150MM; Family and Type: Rectangular Mullion: FAST FELT 150MM; Type Id: 2906568
Constraints - Level: H01
ePset_Simplebim - Assembly Level: Leaf
Phasing - Phase Created: Fase 1 - Som bygget
Pset_QuantityTakeOff - Reference: FAST FELT 150MM
ePset_SimplebimBasicQuantities - Weight, as steel (Simplebim): 186.634 kg; Volume, net (Simplebim): 0.023775 m3; Area, sides, net (Simplebim): 1.283 m2; Width (Simplebim): 50 mm; Length (Simplebim): 150 mm; Height (Simplebim): 3170 mm
Pset_MemberCommon - Reference: FAST FELT 150MM; IsExternal: yes; Span: 3170 mm
Dimensions - Length: 3170 mm; Volume: 0.023775 m3; Area: 0.6415 m2
BaseQuantities - Length: 3170 mm; NetVolume: 0.023775 m3; CrossSectionArea: 0.6415 m2
Name (Rectangular Mullion:FAST FELT 150MM:...) | Host Id
3024242 | 3024238
3030517 | 3024247

# IfcPlate: System Panel:ENZV_Alu innfill 285mm_offset -11, System Panel:ENZV_Alu innfill 285mm_offset -11:3045529
In: H01
Type - PredefinedType: CURTAIN_PANEL; Material: Alusystem isolert infill
Type - Other - Category: Curtain Panels; Family Name: System Panel
Type - Constraints - Offset: -11 mm
Type - Dimensions - Thickness: 284 mm
Type - Identity Data - Type Name: ENZV_Alu innfill 285mm_offset -11; Workset: Family : Curtain Panels : System Panel
Type - Materials and Finishes - Material: Alusystem isolert infill
Type - Analytical Properties - Define Thermal Properties by: Schematic Type; Analytic Construction: <None>
Other - Family and Type: System Panel: ENZV_Alu innfill 285mm_offset -11; Type Id: 2906826; Type: ENZV_Alu innfill 285mm_offset -11; Family: System Panel; Host Id: 3045501
Identity Data - Workset: Workset1
Constraints - Level: H01
Phasing - Phase Created: Fase 1 - Som bygget
ePset_LocationTool - Splitting: ORIGINAL
Pset_PlateCommon - IsExternal: yes; Reference: ENZV_Alu innfill 285mm_offset -11
ePset_Simplebim - Assembly Level: Leaf
Dimensions - Width: 150 mm; Height: 2070 mm; Volume: 0.088182 m3; Area: 0.3105 m2
Pset_QuantityTakeOff - Reference: ENZV_Alu innfill 285mm_offset -11
ePset_SimplebimBasicQuantities - Area, largest surface, net (Simplebim): 0.58788 m2; Weight, as steel (Simplebim): 692.229 kg; Volume, net (Simplebim): 0.088182 m3
BaseQuantities - NetVolume: 0.088182 m3

# IfcPlate: System Panel:ENZV_Alu innfill 285mm_offset 57.5, System Panel:ENZV_Alu innfill 285mm_offset 57.5:3048155
In: H01
Type - PredefinedType: CURTAIN_PANEL; Material: Alusystem isolert infill
Type - Other - Category: Curtain Panels; Family Name: System Panel
Type - Constraints - Offset: 57.5 mm
Type - Dimensions - Thickness: 284 mm
Type - Identity Data - Type Name: ENZV_Alu innfill 285mm_offset 57.5; Workset: Family : Curtain Panels : System Panel
Type - Materials and Finishes - Material: Alusystem isolert infill
Type - Analytical Properties - Define Thermal Properties by: Schematic Type; Analytic Construction: <None>
Other - Family and Type: System Panel: ENZV_Alu innfill 285mm_offset 57.5; Type Id: 2906620; Host Id: 3028790; Type: ENZV_Alu innfill 285mm_offset 57.5; Family: System Panel
Pset_QuantityTakeOff - Reference: ENZV_Alu innfill 285mm_offset 57.5
ePset_LocationTool - Splitting: RESULT
Pset_PlateCommon - IsExternal: yes; Reference: ENZV_Alu innfill 285mm_offset 57.5
Identity Data - Workset: Workset1
Constraints - Level: H01
Phasing - Phase Created: Fase 1 - Som bygget
ePset_Simplebim - Assembly Level: Leaf
ePset_SimplebimBasicQuantities - Volume, net (Simplebim): 0.0715669 m3; Area, largest surface, net (Simplebim): 0.514235 m2; Weight, as steel (Simplebim): 561.8 kg

# IfcPlate: System Panel:Glassfelt 10mm (4)
In: H01
Type - PredefinedType: CURTAIN_PANEL; Material: Glass
Type - Other - Category: Curtain Panels; Family Name: System Panel
Type - Constraints - Offset: 0 mm
Type - Dimensions - Thickness: 10 mm
Type - Identity Data - Type Name: Glassfelt 10mm; Workset: Family : Curtain Panels : System Panel
Type - Materials and Finishes - Material: Glass
Type - Analytical Properties - Define Thermal Properties by: Schematic Type; Analytic Construction: <None>
Pset_QuantityTakeOff - Reference: Glassfelt 10mm
Pset_PlateCommon - Reference: Glassfelt 10mm; IsExternal: yes
Identity Data - Workset: Workset1
Other - Type Id: 128792; Type: Glassfelt 10mm; Family: System Panel; Family and Type: System Panel: Glassfelt 10mm
Constraints - Level: H01
Phasing - Phase Created: Fase 1 - Som bygget
ePset_Simplebim - Assembly Level: Leaf
Name (System Panel:Glassfelt 10mm:...) | Area, largest surface, net (Simplebim) (m2) | Weight, as steel (Simplebim) (kg) | Volume, net (Simplebim) (m3) | Host Id | Splitting | Area (m2) | Height (mm) | Width (mm) | Volume (m3) = NetVolume (m3)
3024239 | 2.5788 | 202.436 | 0.025788 | 3024238 | ORIGINAL | 2.5788 | 3070 | 840 | 0.025788
3024249 | 0.580965 | 45.6058 | 0.00580965 | 3024243 | ORIGINAL | 0.580965 | 166 | 3499.79 | 0.00580965
3024246 | 1.36051 | 106.8 | 0.0136051 | 3024247 | ORIGINAL | 1.36051 | 3070 | 443.164 | 0.0136051
3024263 | 0.120993 | 9.49793 | 0.00120993 | 3024262 | RESULT

# IfcPlate: System Panel:Glassfelt 52mm+103mm ut (19)
In: H01
Type - PredefinedType: CURTAIN_PANEL; Material: Glass
Type - Other - Category: Curtain Panels; Family Name: System Panel
Type - Constraints - Offset: 106 mm
Type - Dimensions - Thickness: 52 mm
Type - Identity Data - Type Name: Glassfelt 52mm+103mm ut; Workset: Family : Curtain Panels : System Panel
Type - Materials and Finishes - Material: Glass
Type - Analytical Properties - Define Thermal Properties by: Schematic Type; Analytic Construction: <None>
Pset_PlateCommon - IsExternal: yes; Reference: Glassfelt 52mm+103mm ut
Other - Family and Type: System Panel: Glassfelt 52mm+103mm ut; Type Id: 2906405; Type: Glassfelt 52mm+103mm ut; Family: System Panel
Constraints - Level: H01
Pset_QuantityTakeOff - Reference: Glassfelt 52mm+103mm ut
Phasing - Phase Created: Fase 1 - Som bygget
ePset_LocationTool - Splitting: RESULT
ePset_Simplebim - Assembly Level: Leaf
Name (System Panel:Glassfelt 52mm+103mm ut:...) | Host Id | Workset | Weight, as steel (Simplebim) (kg) | Area, largest surface, net (Simplebim) (m2) | Volume, net (Simplebim) (m3)
3045591 | 3045579 | Workset1 | 2450.22 | 6.0025 | 0.31213
3045608 | 3045609 | Workset1 | 2315.69 | 5.67293 | 0.294993
3045627 | 3045628 | Workset1 | 2450.16 | 6.00236 | 0.312123
3045649 | 3045650 | Workset1 | 2315.66 | 5.67286 | 0.294989
4091192 | 4091180 | ARK - Innvendige arbeider | 2245.98 | 6.00236 | 0.286113
4091194 | 4091180 | ARK - Innvendige arbeider | 2245.98 | 6.00236 | 0.286113
4091196 | 4091180 | ARK - Innvendige arbeider | 2245.98 | 6.00236 | 0.286113
4091198 | 4091180 | ARK - Innvendige arbeider | 2245.98 | 6.00236 | 0.286113
4091200 | 4091180 | ARK - Innvendige arbeider | 2245.98 | 6.00236 | 0.286113
4091202 | 4091180 | ARK - Innvendige arbeider | 2245.98 | 6.00236 | 0.286113
4091204 | 4091180 | ARK - Innvendige arbeider | 2245.98 | 6.00236 | 0.286113
3038595 | 3038579 | Workset1 | 2373.13 | 5.81365 | 0.302309
3045455 | 3045456 | Workset1 | 2450.16 | 6.00236 | 0.312123
3045475 | 3045476 | Workset1 | 2450.16 | 6.00236 | 0.312123
3045523 | 3045501 | Workset1 | 971.516 | 2.38 | 0.12376
4091206 | 4091180 | ARK - Innvendige arbeider | 2245.98 | 6.00236 | 0.286113
4091208 | 4091180 | ARK - Innvendige arbeider | 2245.98 | 6.00236 | 0.286113
4091210 | 4091180 | ARK - Innvendige arbeider | 2245.98 | 6.00236 | 0.286113
4091212 | 4091180 | ARK - Innvendige arbeider | 2245.98 | 6.00236 | 0.286113

# IfcPlate: System Panel:Glassfelt Alu 50mm Skytedør Inne, System Panel:Glassfelt Alu 50mm Skytedør Inne:3024252
In: H01
Type - PredefinedType: CURTAIN_PANEL; Material: Aluminium
Type - Other - Category: Curtain Panels; Family Name: System Panel
Type - Constraints - Offset: 0 mm
Type - Dimensions - Thickness: 50 mm
Type - Identity Data - Type Name: Glassfelt Alu 50mm Skytedør Inne; Workset: Family : Curtain Panels : System Panel
Type - Materials and Finishes - Material: Aluminium
Type - Analytical Properties - Define Thermal Properties by: Schematic Type; Analytic Construction: <None>
Pset_QuantityTakeOff - Reference: Glassfelt Alu 50mm Skytedør Inne
Pset_PlateCommon - IsExternal: yes; Reference: Glassfelt Alu 50mm Skytedør Inne
Identity Data - Workset: Workset1
ePset_LocationTool - Splitting: ORIGINAL
ePset_SimplebimBasicQuantities - Weight, as steel (Simplebim): 274.733 kg; Area, largest surface, net (Simplebim): 0.699958 m2; Volume, net (Simplebim): 0.0349979 m3
Constraints - Level: H01
Other - Family and Type: System Panel: Glassfelt Alu 50mm Skytedør Inne; Family: System Panel; Type Id: 2906431; Host Id: 3024243; Type: Glassfelt Alu 50mm Skytedør Inne
Phasing - Phase Created: Fase 1 - Som bygget
ePset_Simplebim - Assembly Level: Leaf
Dimensions - Area: 0.699958 m2; Height: 200 mm; Volume: 0.0349979 m3; Width: 3499.79 mm
BaseQuantities - NetVolume: 0.0349979 m3

# IfcSlab: Floor:ENZV_G04_Flis mørk grå 15mm, Floor:ENZV_G04_Flis mørk grå 15mm:3031216
In: H01
Type - PredefinedType: FLOOR; Material: Fliser 600x600mm mørk grå 15 mm
Type - Other - Category: Floors; Family Name: Floor
Type - Construction - Function: Interior; Default Thickness: 15 mm
Type - Graphics - Coarse Scale Fill Color: 0
Type - Identity Data - Type Name: ENZV_G04_Flis mørk grå 15mm; Workset: Floor Types; Type Mark: ENZV_G04
Type - Analytical Properties - Absorptance: 0.1; Roughness: 1
Type - Materials and Finishes - Structural Material: Fliser 600x600mm mørk grå
Pset_QuantityTakeOff - Reference: ENZV_G04_Flis mørk grå 15mm; sets with these values: 2
Pset_SlabCommon - Reference: ENZV_G04_Flis mørk grå 15mm; LoadBearing: no; IsExternal: no
Other - Type Id: 2906451; Type: ENZV_G04_Flis mørk grå 15mm; Family and Type: Floor: ENZV_G04_Flis mørk grå 15mm; Family: Floor
Identity Data - Has Association: no; Workset: Workset1
Phasing - Phase Created: Fase 1 - Som bygget
ePset_SimplebimBasicQuantities - Volume, net (Simplebim): 2.16178 m3; Area, largest surface, net (Simplebim): 144.118 m2; Perimeter (Simplebim): 68093.7 mm; Thickness (Simplebim): 15 mm; Area, sides, net (Simplebim): 1.02141 m2; Area, top, net (Simplebim): 144.118 m2
ePset_LocationTool - Splitting: RESULT
Constraints - Related to Mass: no; Room Bounding: no; Level: H01
ePset_Simplebim - Assembly Level: Leaf
Structural - Structural: no

# IfcWall: Basic Wall:ENZV_S-UK10_T98_150mm_OSBG, Basic Wall:ENZV_S-UK10_T98_150mm_OSBG:3024171
In: H01
Type - PredefinedType: STANDARD; Material: A246.Gips 12.5mm fiberarmert -QK5.31112 13 mm, OSB plate 12 mm, Stender/Isolasjon 100 mm, OSB plate 12 mm, A246.Gips 12.5mm fiberarmert -QK5.31112 13 mm
Type - Other - Category: Walls; Family Name: Basic Wall
Type - Construction - Function: Interior; Width: 150 mm; Wrapping at Inserts: Do not wrap; CQMaxWallHeight: 6000 mm
Type - Graphics - Coarse Scale Fill Color: 0
Type - Identity Data - Type Name: ENZV_S-UK10_T98_150mm_OSBG; Workset: Wall Types; Type Mark: S-UK10
Type - Analytical Properties - Absorptance: 0.1; Roughness: 1
Type - Materials and Finishes - Structural Material: Stender/Isolasjon
Type - Text - Veggtype S: ENZV_S-UK10_T98_155mm_OSBG
Phasing - Phase Created: Fase 1 - Som bygget
Pset_WallCommon - Reference: ENZV_S-UK10_T98_150mm_OSBG; IsExternal: no; ExtendToStructure: no; LoadBearing: no
Cross-Section Definition - Cross-Section: Vertical
Structural - Structural Usage: Non-bearing; Structural: no
ePset_LocationTool - Splitting: RESULT
ePset_SimplebimBasicQuantities - Area, side, net, average (Simplebim): 1.15272 m2; Area, side, gross, average (Simplebim): 1.15272 m2; Area, side, gross, AABB (Simplebim): 1.2036 m2; Area, largest surface, net (Simplebim): 1.20372 m2; Area, side, net, larger (Simplebim): 1.20372 m2; Area, side, gross, larger (Simplebim): 1.20372 m2; Thickness (Simplebim): 150 mm; Height (Simplebim): 680 mm; Length (Simplebim): 1770 mm; Area, side, gross, smaller (Simplebim): 1.10171 m2; Area, side, net, smaller (Simplebim): 1.10171 m2; Volume, net (Simplebim): 0.172907 m3
Identity Data - Workset: Workset1
Pset_ReinforcementBarPitchOfWall - Reference: ENZV_S-UK10_T98_150mm_OSBG; sets with these values: 2
Other - Family and Type: Basic Wall: ENZV_S-UK10_T98_150mm_OSBG; Family: Basic Wall; Type: ENZV_S-UK10_T98_150mm_OSBG; Type Id: 2906425
ePset_Simplebim - Assembly Level: Leaf
Constraints - Location Line: Wall Centerline; Base is Attached: no; Related to Mass: no; Room Bounding: yes; Top is Attached: no; Base Constraint: H01; Top Constraint: Up to level: H02
